VERSION 5.7 ;

  DIVIDERCHAR "/" ;
  BUSBITCHARS "[]" ;
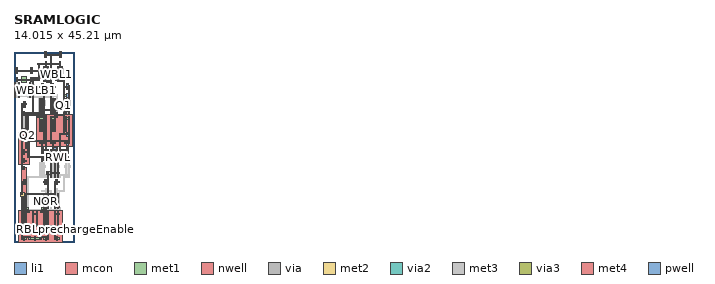
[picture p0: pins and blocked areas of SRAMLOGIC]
MACRO SRAMLOGIC
  CLASS BLOCK ;
  FOREIGN SRAMLOGIC ;
  ORIGIN -0.605 0.000 ;
  SIZE 14.015 BY 45.210 ;
  PIN WWL
    ANTENNAGATEAREA 1.008000 ;
    PORT
      LAYER li1 ;
        RECT 1.165 38.135 1.415 39.145 ;
        RECT 4.605 38.135 4.855 39.145 ;
        RECT 6.325 38.555 6.575 42.505 ;
        RECT 8.045 41.915 8.295 42.925 ;
        RECT 11.485 41.915 11.735 42.925 ;
      LAYER mcon ;
        RECT 6.365 42.335 6.535 42.505 ;
        RECT 1.205 38.555 1.375 38.725 ;
        RECT 4.645 38.555 4.815 38.725 ;
        RECT 8.085 42.335 8.255 42.505 ;
        RECT 11.525 42.335 11.695 42.505 ;
        RECT 6.365 38.555 6.535 38.725 ;
      LAYER met1 ;
        RECT 6.280 42.280 11.780 42.560 ;
        RECT 2.380 38.780 3.550 39.270 ;
        RECT 1.120 38.500 6.620 38.780 ;
        RECT 2.380 37.980 3.550 38.500 ;
    END
  END WWL
  PIN VDD
    ANTENNADIFFAREA 3.749200 ;
    PORT
      LAYER nwell ;
        RECT 1.720 18.480 4.300 26.040 ;
        RECT 6.020 22.680 14.620 30.240 ;
        RECT 11.000 22.670 12.420 22.680 ;
        RECT 1.720 0.000 12.040 7.560 ;
      LAYER li1 ;
        RECT 6.755 26.375 7.005 29.905 ;
        RECT 7.615 26.375 7.865 29.905 ;
        RECT 9.335 26.375 9.585 29.905 ;
        RECT 10.195 26.375 10.445 29.905 ;
        RECT 12.775 26.375 13.025 29.905 ;
        RECT 13.635 26.375 13.885 29.905 ;
        RECT 2.455 22.175 2.705 25.705 ;
        RECT 3.315 22.175 3.565 25.705 ;
        RECT 7.185 23.015 7.435 24.025 ;
        RECT 9.765 23.015 10.015 24.025 ;
        RECT 13.205 23.015 13.455 24.025 ;
        RECT 2.885 18.815 3.135 19.825 ;
        RECT 2.455 3.695 2.705 7.225 ;
        RECT 3.315 3.695 3.565 7.225 ;
        RECT 7.615 3.695 7.865 7.225 ;
        RECT 8.475 3.695 8.725 7.225 ;
        RECT 10.195 3.695 10.445 7.225 ;
        RECT 11.055 3.695 11.305 7.225 ;
        RECT 2.885 0.335 3.135 1.345 ;
        RECT 5.465 0.335 5.715 1.345 ;
        RECT 8.045 0.335 8.295 1.345 ;
        RECT 10.625 0.335 10.875 1.345 ;
      LAYER mcon ;
        RECT 6.795 29.315 6.965 29.485 ;
        RECT 7.655 29.315 7.825 29.485 ;
        RECT 9.375 29.315 9.545 29.485 ;
        RECT 10.235 29.315 10.405 29.485 ;
        RECT 12.815 29.315 12.985 29.485 ;
        RECT 13.675 29.315 13.845 29.485 ;
        RECT 2.495 25.115 2.665 25.285 ;
        RECT 3.355 25.115 3.525 25.285 ;
        RECT 7.225 23.435 7.395 23.605 ;
        RECT 9.805 23.435 9.975 23.605 ;
        RECT 13.245 23.435 13.415 23.605 ;
        RECT 2.925 19.235 3.095 19.405 ;
        RECT 2.495 6.635 2.665 6.805 ;
        RECT 3.355 6.635 3.525 6.805 ;
        RECT 7.655 6.635 7.825 6.805 ;
        RECT 8.515 6.635 8.685 6.805 ;
        RECT 10.235 6.635 10.405 6.805 ;
        RECT 11.095 6.635 11.265 6.805 ;
        RECT 2.925 0.755 3.095 0.925 ;
        RECT 5.505 0.755 5.675 0.925 ;
        RECT 8.085 0.755 8.255 0.925 ;
        RECT 10.665 0.755 10.835 0.925 ;
      LAYER met1 ;
        RECT 6.710 29.260 7.910 29.540 ;
        RECT 9.290 29.260 10.490 29.540 ;
        RECT 12.730 29.260 13.930 29.540 ;
        RECT 2.410 25.060 3.610 25.340 ;
        RECT 2.420 23.800 13.920 24.080 ;
        RECT 6.710 23.380 7.910 23.660 ;
        RECT 9.290 23.380 10.490 23.660 ;
        RECT 12.730 23.380 13.930 23.660 ;
        RECT 2.410 19.180 3.610 19.460 ;
        RECT 2.410 6.580 3.610 6.860 ;
        RECT 7.570 6.580 8.770 6.860 ;
        RECT 10.150 6.580 11.350 6.860 ;
        RECT 8.440 3.640 10.480 3.920 ;
        RECT 2.420 1.120 4.460 1.400 ;
        RECT 6.720 1.120 8.760 1.400 ;
        RECT 4.660 0.980 5.210 1.110 ;
        RECT 2.410 0.700 3.610 0.980 ;
        RECT 4.140 0.700 7.040 0.980 ;
        RECT 7.570 0.700 8.770 0.980 ;
        RECT 10.150 0.700 11.350 0.980 ;
        RECT 4.660 0.510 5.210 0.700 ;
      LAYER via ;
        RECT 7.610 29.270 7.870 29.530 ;
        RECT 9.330 29.270 9.590 29.530 ;
        RECT 13.630 29.270 13.890 29.530 ;
        RECT 2.450 25.070 2.710 25.330 ;
        RECT 2.450 23.810 2.710 24.070 ;
        RECT 7.610 23.810 7.870 24.070 ;
        RECT 9.330 23.810 9.590 24.070 ;
        RECT 13.630 23.810 13.890 24.070 ;
        RECT 7.610 23.390 7.870 23.650 ;
        RECT 9.330 23.390 9.590 23.650 ;
        RECT 13.630 23.390 13.890 23.650 ;
        RECT 2.450 19.190 2.710 19.450 ;
        RECT 2.450 6.590 2.710 6.850 ;
        RECT 8.470 6.590 8.730 6.850 ;
        RECT 10.190 6.590 10.450 6.850 ;
        RECT 8.470 3.650 8.730 3.910 ;
        RECT 10.190 3.650 10.450 3.910 ;
        RECT 2.450 1.130 2.710 1.390 ;
        RECT 4.170 1.130 4.430 1.390 ;
        RECT 6.750 1.130 7.010 1.390 ;
        RECT 8.470 1.130 8.730 1.390 ;
        RECT 2.450 0.710 2.710 0.970 ;
        RECT 4.170 0.710 4.430 0.970 ;
        RECT 6.750 0.710 7.010 0.970 ;
        RECT 8.470 0.710 8.730 0.970 ;
        RECT 10.190 0.710 10.450 0.970 ;
      LAYER met2 ;
        RECT 2.440 17.455 2.720 25.360 ;
        RECT 7.600 23.360 7.880 29.560 ;
        RECT 9.320 23.360 9.600 29.560 ;
        RECT 13.620 23.360 13.900 29.560 ;
        RECT 2.440 0.680 2.720 7.745 ;
        RECT 4.160 0.680 4.440 1.420 ;
        RECT 6.740 0.680 7.020 1.420 ;
        RECT 8.460 0.680 8.740 6.880 ;
        RECT 10.180 0.680 10.460 6.880 ;
      LAYER via2 ;
        RECT 2.440 17.500 2.720 17.780 ;
        RECT 2.440 7.420 2.720 7.700 ;
      LAYER met3 ;
        RECT 2.415 17.240 3.125 18.040 ;
        RECT 2.415 7.160 3.125 7.960 ;
      LAYER via3 ;
        RECT 2.800 17.480 3.120 17.800 ;
        RECT 2.800 7.400 3.120 7.720 ;
      LAYER met4 ;
        RECT 2.370 7.395 3.550 17.805 ;
    END
  END VDD
  PIN WBLB1
    ANTENNADIFFAREA 0.445200 ;
    PORT
      LAYER li1 ;
        RECT 4.175 34.355 4.425 37.885 ;
        RECT 5.035 34.355 5.285 37.885 ;
      LAYER mcon ;
        RECT 4.215 35.195 4.385 35.365 ;
        RECT 5.075 35.195 5.245 35.365 ;
      LAYER met1 ;
        RECT 4.490 35.420 5.040 35.650 ;
        RECT 4.130 35.140 5.330 35.420 ;
    END
  END WBLB1
  PIN WBL2
    ANTENNADIFFAREA 0.235200 ;
    PORT
      LAYER li1 ;
        RECT 8.045 38.135 8.295 41.665 ;
      LAYER mcon ;
        RECT 8.085 38.135 8.255 38.305 ;
      LAYER met1 ;
        RECT 8.350 38.360 8.970 38.520 ;
        RECT 8.000 38.080 9.200 38.360 ;
        RECT 8.350 37.900 8.970 38.080 ;
    END
  END WBL2
  PIN WBL1
    ANTENNADIFFAREA 0.235200 ;
    PORT
      LAYER li1 ;
        RECT 11.485 38.135 11.735 41.665 ;
      LAYER mcon ;
        RECT 11.525 38.555 11.695 38.725 ;
      LAYER met1 ;
        RECT 10.890 38.780 11.340 38.850 ;
        RECT 10.580 38.500 11.780 38.780 ;
        RECT 10.890 38.390 11.340 38.500 ;
    END
  END WBL1
  PIN WBLB2
    ANTENNADIFFAREA 0.445200 ;
    PORT
      LAYER li1 ;
        RECT 0.735 34.355 0.985 37.885 ;
        RECT 1.595 34.355 1.845 37.885 ;
      LAYER mcon ;
        RECT 0.775 35.615 0.945 35.785 ;
        RECT 1.635 35.615 1.805 35.785 ;
      LAYER met1 ;
        RECT 0.950 35.840 1.600 35.990 ;
        RECT 0.690 35.560 1.890 35.840 ;
        RECT 0.950 35.340 1.600 35.560 ;
    END
  END WBLB2
  PIN GND
    ANTENNADIFFAREA 5.644800 ;
    PORT
      LAYER pwell ;
        RECT 7.955 43.830 8.385 45.210 ;
        RECT 11.395 43.830 11.825 45.210 ;
        RECT 1.075 40.050 1.505 41.430 ;
        RECT 4.515 40.050 4.945 41.430 ;
        RECT 7.095 36.270 7.525 37.650 ;
        RECT 9.675 36.270 10.105 37.650 ;
        RECT 13.115 36.270 13.545 37.650 ;
        RECT 2.795 32.070 3.225 33.450 ;
        RECT 7.095 21.150 7.525 22.530 ;
        RECT 9.675 21.150 10.965 22.530 ;
        RECT 13.115 21.150 13.545 22.530 ;
        RECT 2.795 13.590 3.225 14.970 ;
        RECT 7.955 13.590 8.385 14.970 ;
        RECT 10.535 13.590 10.965 14.970 ;
      LAYER li1 ;
        RECT 8.045 44.015 8.295 45.025 ;
        RECT 11.485 44.015 11.735 45.025 ;
        RECT 1.165 40.235 1.415 41.245 ;
        RECT 4.605 40.235 4.855 41.245 ;
        RECT 7.185 36.455 7.435 37.465 ;
        RECT 9.765 36.455 10.015 37.465 ;
        RECT 13.205 36.455 13.455 37.465 ;
        RECT 2.885 32.255 3.135 33.265 ;
        RECT 6.755 30.575 7.005 34.105 ;
        RECT 7.615 30.575 7.865 34.105 ;
        RECT 9.335 30.575 9.585 34.105 ;
        RECT 10.195 30.575 10.445 34.105 ;
        RECT 12.775 30.575 13.025 34.105 ;
        RECT 13.635 30.575 13.885 34.105 ;
        RECT 2.455 26.375 2.705 29.905 ;
        RECT 3.315 26.375 3.565 29.905 ;
        RECT 7.185 21.335 7.435 22.345 ;
        RECT 8.475 21.335 8.725 21.925 ;
        RECT 9.765 21.335 10.015 22.345 ;
        RECT 10.625 21.335 10.875 22.345 ;
        RECT 11.485 21.335 11.735 21.925 ;
        RECT 13.205 21.335 13.455 22.345 ;
        RECT 9.335 15.455 9.585 18.985 ;
        RECT 10.195 15.455 10.445 18.985 ;
        RECT 11.055 15.455 11.305 18.985 ;
        RECT 2.885 13.775 3.135 14.785 ;
        RECT 8.045 13.775 8.295 14.785 ;
        RECT 10.625 13.775 10.875 14.785 ;
        RECT 2.455 7.895 2.705 11.425 ;
        RECT 3.315 7.895 3.565 11.425 ;
        RECT 7.615 7.895 7.865 11.425 ;
        RECT 8.475 7.895 8.725 11.425 ;
        RECT 10.195 7.895 10.445 11.425 ;
        RECT 11.055 7.895 11.305 11.425 ;
      LAYER mcon ;
        RECT 8.085 44.435 8.255 44.605 ;
        RECT 11.525 44.435 11.695 44.605 ;
        RECT 1.205 40.655 1.375 40.825 ;
        RECT 4.645 40.655 4.815 40.825 ;
        RECT 7.225 36.875 7.395 37.045 ;
        RECT 9.805 36.875 9.975 37.045 ;
        RECT 13.245 36.875 13.415 37.045 ;
        RECT 2.925 32.675 3.095 32.845 ;
        RECT 6.795 30.995 6.965 31.165 ;
        RECT 7.655 30.995 7.825 31.165 ;
        RECT 9.375 30.995 9.545 31.165 ;
        RECT 10.235 30.995 10.405 31.165 ;
        RECT 12.815 30.995 12.985 31.165 ;
        RECT 13.675 30.995 13.845 31.165 ;
        RECT 2.495 26.795 2.665 26.965 ;
        RECT 3.355 26.795 3.525 26.965 ;
        RECT 7.225 21.755 7.395 21.925 ;
        RECT 8.515 21.755 8.685 21.925 ;
        RECT 8.515 21.335 8.685 21.505 ;
        RECT 9.805 21.755 9.975 21.925 ;
        RECT 10.665 21.755 10.835 21.925 ;
        RECT 11.525 21.755 11.695 21.925 ;
        RECT 11.525 21.335 11.695 21.505 ;
        RECT 13.245 21.755 13.415 21.925 ;
        RECT 9.375 16.295 9.545 16.465 ;
        RECT 10.235 16.295 10.405 16.465 ;
        RECT 11.095 16.295 11.265 16.465 ;
        RECT 2.925 14.195 3.095 14.365 ;
        RECT 8.085 14.195 8.255 14.365 ;
        RECT 10.665 14.195 10.835 14.365 ;
        RECT 2.495 8.315 2.665 8.485 ;
        RECT 3.355 8.315 3.525 8.485 ;
        RECT 7.655 8.315 7.825 8.485 ;
        RECT 8.515 8.315 8.685 8.485 ;
        RECT 10.235 8.315 10.405 8.485 ;
        RECT 11.095 8.315 11.265 8.485 ;
      LAYER met1 ;
        RECT 8.000 44.380 11.780 44.660 ;
        RECT 2.550 40.880 3.280 40.890 ;
        RECT 1.120 40.600 9.620 40.880 ;
        RECT 2.550 40.590 3.280 40.600 ;
        RECT 6.710 36.820 7.910 37.100 ;
        RECT 9.290 36.820 10.490 37.100 ;
        RECT 12.730 36.820 13.930 37.100 ;
        RECT 2.410 32.620 3.610 32.900 ;
        RECT 7.580 31.360 13.920 31.640 ;
        RECT 6.710 30.940 7.910 31.220 ;
        RECT 9.290 30.940 10.490 31.220 ;
        RECT 12.730 30.940 13.930 31.220 ;
        RECT 2.420 30.100 8.330 30.380 ;
        RECT 2.410 26.740 3.610 27.020 ;
        RECT 7.140 21.700 8.770 21.980 ;
        RECT 9.290 21.700 10.920 21.980 ;
        RECT 11.440 21.700 13.500 21.980 ;
        RECT 8.430 21.280 11.780 21.560 ;
        RECT 9.290 16.240 11.350 16.520 ;
        RECT 2.410 14.140 3.610 14.420 ;
        RECT 7.570 14.140 8.770 14.420 ;
        RECT 10.150 14.140 11.350 14.420 ;
        RECT 2.420 11.200 10.480 11.480 ;
        RECT 2.410 8.260 3.610 8.540 ;
        RECT 7.570 8.260 8.770 8.540 ;
        RECT 10.150 8.260 11.350 8.540 ;
      LAYER via ;
        RECT 9.330 44.390 9.590 44.650 ;
        RECT 9.330 40.610 9.590 40.870 ;
        RECT 7.610 36.830 7.870 37.090 ;
        RECT 9.330 36.830 9.590 37.090 ;
        RECT 13.630 36.830 13.890 37.090 ;
        RECT 2.450 32.630 2.710 32.890 ;
        RECT 7.610 31.370 7.870 31.630 ;
        RECT 9.330 31.370 9.590 31.630 ;
        RECT 13.630 31.370 13.890 31.630 ;
        RECT 7.610 30.950 7.870 31.210 ;
        RECT 9.330 30.950 9.590 31.210 ;
        RECT 13.630 30.950 13.890 31.210 ;
        RECT 2.450 30.110 2.710 30.370 ;
        RECT 7.610 30.110 7.870 30.370 ;
        RECT 8.040 30.110 8.300 30.370 ;
        RECT 2.450 26.750 2.710 27.010 ;
        RECT 8.040 21.710 8.300 21.970 ;
        RECT 9.330 21.710 9.590 21.970 ;
        RECT 9.330 21.290 9.590 21.550 ;
        RECT 9.330 16.250 9.590 16.510 ;
        RECT 2.450 14.150 2.710 14.410 ;
        RECT 8.470 14.150 8.730 14.410 ;
        RECT 10.190 14.150 10.450 14.410 ;
        RECT 2.450 11.210 2.710 11.470 ;
        RECT 8.470 11.210 8.730 11.470 ;
        RECT 10.190 11.210 10.450 11.470 ;
        RECT 2.450 8.270 2.710 8.530 ;
        RECT 8.470 8.270 8.730 8.530 ;
        RECT 10.190 8.270 10.450 8.530 ;
      LAYER met2 ;
        RECT 2.440 26.720 2.720 32.920 ;
        RECT 7.600 30.080 7.880 37.120 ;
        RECT 9.320 30.920 9.600 44.680 ;
        RECT 13.620 30.920 13.900 37.120 ;
        RECT 8.030 21.680 8.310 30.400 ;
        RECT 2.440 11.670 2.720 14.440 ;
        RECT 2.090 10.930 2.990 11.670 ;
        RECT 2.440 8.240 2.720 10.930 ;
        RECT 8.460 8.240 8.740 16.565 ;
        RECT 9.320 16.195 9.600 22.000 ;
        RECT 10.180 8.240 10.460 14.440 ;
      LAYER via2 ;
        RECT 8.460 16.240 8.740 16.520 ;
        RECT 9.320 16.240 9.600 16.520 ;
      LAYER met3 ;
        RECT 8.435 15.980 9.625 16.780 ;
    END
  END GND
  PIN Q1
    ANTENNAGATEAREA 0.504000 ;
    ANTENNADIFFAREA 0.798000 ;
    PORT
      LAYER li1 ;
        RECT 11.055 38.135 11.305 41.665 ;
        RECT 11.915 38.135 12.165 41.665 ;
        RECT 9.765 30.575 10.015 34.105 ;
        RECT 9.765 26.375 10.015 29.905 ;
        RECT 12.345 25.535 12.595 39.565 ;
        RECT 13.205 34.355 13.455 35.365 ;
        RECT 13.205 25.115 13.455 26.125 ;
        RECT 10.625 19.235 10.875 20.245 ;
      LAYER mcon ;
        RECT 11.095 39.395 11.265 39.565 ;
        RECT 11.955 39.395 12.125 39.565 ;
        RECT 12.385 39.395 12.555 39.565 ;
        RECT 12.385 34.775 12.555 34.945 ;
        RECT 9.805 30.575 9.975 30.745 ;
        RECT 13.245 34.775 13.415 34.945 ;
        RECT 12.385 30.155 12.555 30.325 ;
        RECT 9.805 29.735 9.975 29.905 ;
        RECT 12.385 25.535 12.555 25.705 ;
        RECT 13.245 25.535 13.415 25.705 ;
        RECT 10.665 19.655 10.835 19.825 ;
      LAYER met1 ;
        RECT 11.010 39.340 12.640 39.620 ;
        RECT 12.300 34.720 13.500 35.000 ;
        RECT 9.720 30.520 10.920 30.800 ;
        RECT 10.160 30.100 12.640 30.380 ;
        RECT 9.720 29.680 10.920 29.960 ;
        RECT 11.450 25.480 13.500 25.760 ;
        RECT 10.580 19.600 11.780 19.880 ;
        RECT 11.030 19.300 11.480 19.600 ;
      LAYER via ;
        RECT 10.190 30.530 10.450 30.790 ;
        RECT 10.190 30.110 10.450 30.370 ;
        RECT 10.190 29.690 10.450 29.950 ;
        RECT 11.480 25.490 11.740 25.750 ;
        RECT 11.480 19.610 11.740 19.870 ;
      LAYER met2 ;
        RECT 10.180 29.660 10.460 30.820 ;
        RECT 11.470 19.580 11.750 25.780 ;
    END
  END Q1
  PIN Q2
    ANTENNAGATEAREA 0.504000 ;
    ANTENNADIFFAREA 0.798000 ;
    PORT
      LAYER li1 ;
        RECT 7.615 38.135 7.865 41.665 ;
        RECT 8.475 38.135 8.725 41.665 ;
        RECT 2.885 30.155 3.135 31.165 ;
        RECT 2.885 20.915 3.135 21.925 ;
        RECT 3.745 20.075 3.995 30.745 ;
        RECT 5.035 30.575 5.285 34.105 ;
        RECT 7.185 30.575 7.435 34.105 ;
        RECT 7.185 26.375 7.435 29.905 ;
        RECT 9.765 19.235 10.015 20.245 ;
      LAYER mcon ;
        RECT 7.655 38.975 7.825 39.145 ;
        RECT 8.515 38.975 8.685 39.145 ;
        RECT 5.075 33.935 5.245 34.105 ;
        RECT 2.925 30.575 3.095 30.745 ;
        RECT 3.785 30.575 3.955 30.745 ;
        RECT 5.075 30.575 5.245 30.745 ;
        RECT 7.225 30.575 7.395 30.745 ;
        RECT 2.925 21.335 3.095 21.505 ;
        RECT 7.225 29.735 7.395 29.905 ;
        RECT 3.785 21.335 3.955 21.505 ;
        RECT 3.785 20.075 3.955 20.245 ;
        RECT 9.805 20.075 9.975 20.245 ;
      LAYER met1 ;
        RECT 5.000 38.920 8.770 39.200 ;
        RECT 4.990 33.880 5.330 34.160 ;
        RECT 2.840 30.520 7.480 30.800 ;
        RECT 6.280 29.680 7.480 29.960 ;
        RECT 2.840 21.280 4.040 21.560 ;
        RECT 10.120 20.300 10.570 20.910 ;
        RECT 3.700 20.020 10.920 20.300 ;
      LAYER via ;
        RECT 5.030 38.930 5.290 39.190 ;
        RECT 5.030 33.890 5.290 34.150 ;
        RECT 6.750 30.530 7.010 30.790 ;
        RECT 6.750 29.690 7.010 29.950 ;
      LAYER met2 ;
        RECT 5.020 33.860 5.300 39.220 ;
        RECT 6.740 29.660 7.020 30.820 ;
    END
  END Q2
  PIN RWL
    ANTENNAGATEAREA 0.252000 ;
    PORT
      LAYER li1 ;
        RECT 7.185 19.235 7.435 20.245 ;
        RECT 13.205 19.235 13.455 20.245 ;
      LAYER mcon ;
        RECT 7.225 19.655 7.395 19.825 ;
        RECT 13.245 19.655 13.415 19.825 ;
      LAYER met1 ;
        RECT 7.140 19.600 10.050 19.880 ;
        RECT 12.300 19.600 13.500 19.880 ;
        RECT 7.710 19.430 8.320 19.600 ;
      LAYER via ;
        RECT 9.760 19.610 10.020 19.870 ;
        RECT 12.340 19.610 12.600 19.870 ;
      LAYER met2 ;
        RECT 9.750 19.580 10.030 20.345 ;
        RECT 12.330 19.580 12.610 20.345 ;
      LAYER via2 ;
        RECT 9.750 20.020 10.030 20.300 ;
        RECT 12.330 20.020 12.610 20.300 ;
      LAYER met3 ;
        RECT 9.725 19.760 12.635 20.560 ;
    END
  END RWL
  PIN RBLprechargeEnable
    ANTENNAGATEAREA 0.252000 ;
    PORT
      LAYER li1 ;
        RECT 5.465 2.435 5.715 3.445 ;
      LAYER mcon ;
        RECT 5.505 2.855 5.675 3.025 ;
      LAYER met1 ;
        RECT 4.550 3.080 5.070 3.220 ;
        RECT 4.550 2.800 5.760 3.080 ;
        RECT 4.550 2.620 5.070 2.800 ;
    END
  END RBLprechargeEnable
  PIN RBLprecharge
    ANTENNADIFFAREA 0.445200 ;
    PORT
      LAYER li1 ;
        RECT 5.035 3.695 5.285 7.225 ;
        RECT 5.895 3.695 6.145 7.225 ;
      LAYER mcon ;
        RECT 5.075 6.635 5.245 6.805 ;
        RECT 5.935 6.635 6.105 6.805 ;
      LAYER met1 ;
        RECT 4.990 6.580 6.190 6.860 ;
        RECT 5.380 6.470 5.800 6.580 ;
    END
  END RBLprecharge
  PIN NOR
    ANTENNADIFFAREA 0.352800 ;
    PORT
      LAYER li1 ;
        RECT 8.045 7.895 8.295 11.425 ;
        RECT 8.045 3.695 8.295 7.225 ;
      LAYER mcon ;
        RECT 8.085 7.895 8.255 8.065 ;
        RECT 8.085 7.055 8.255 7.225 ;
      LAYER met1 ;
        RECT 7.140 7.840 8.340 8.120 ;
        RECT 6.960 7.000 8.340 7.280 ;
        RECT 6.960 6.960 7.330 7.000 ;
      LAYER via ;
        RECT 7.610 7.850 7.870 8.110 ;
        RECT 7.610 7.010 7.870 7.270 ;
      LAYER met2 ;
        RECT 7.600 6.980 7.880 8.140 ;
    END
  END NOR
  PIN OR
    ANTENNADIFFAREA 0.352800 ;
    PORT
      LAYER li1 ;
        RECT 2.885 7.895 3.135 11.425 ;
        RECT 2.885 3.695 3.135 7.225 ;
      LAYER mcon ;
        RECT 2.925 7.895 3.095 8.065 ;
        RECT 2.925 7.055 3.095 7.225 ;
      LAYER met1 ;
        RECT 2.840 7.840 4.040 8.120 ;
        RECT 2.840 7.000 4.290 7.280 ;
        RECT 3.810 6.930 4.290 7.000 ;
      LAYER via ;
        RECT 3.310 7.850 3.570 8.110 ;
        RECT 3.310 7.010 3.570 7.270 ;
      LAYER met2 ;
        RECT 3.300 6.980 3.580 8.140 ;
    END
  END OR
  OBS
      LAYER pwell ;
        RECT 7.485 40.085 8.855 41.185 ;
        RECT 10.925 40.085 12.295 41.185 ;
        RECT 0.605 36.305 1.975 37.405 ;
        RECT 4.045 36.305 5.415 37.405 ;
        RECT 6.625 32.525 7.995 33.625 ;
        RECT 9.205 32.525 10.575 33.625 ;
        RECT 12.645 32.525 14.015 33.625 ;
        RECT 2.325 28.325 3.695 29.425 ;
        RECT 6.625 17.615 7.995 18.295 ;
        RECT 9.205 17.615 11.435 18.295 ;
        RECT 12.645 17.615 14.015 18.295 ;
        RECT 2.325 10.055 3.695 10.735 ;
        RECT 7.485 10.055 8.855 10.735 ;
        RECT 10.065 10.055 11.435 10.735 ;
      LAYER li1 ;
        RECT 1.165 34.355 1.415 37.885 ;
        RECT 4.605 34.355 4.855 37.885 ;
        RECT 2.885 26.375 3.135 29.905 ;
        RECT 2.885 22.175 3.135 25.705 ;
        RECT 6.325 25.535 6.575 34.945 ;
        RECT 7.185 34.355 7.435 35.365 ;
        RECT 9.765 34.355 10.015 35.365 ;
        RECT 7.185 25.115 7.435 26.125 ;
        RECT 9.765 25.115 10.015 26.125 ;
        RECT 10.625 25.535 10.875 34.945 ;
        RECT 13.205 30.575 13.455 34.105 ;
        RECT 13.205 26.375 13.455 29.905 ;
        RECT 2.885 11.675 3.135 12.685 ;
        RECT 2.885 2.435 3.135 3.445 ;
        RECT 3.745 2.855 3.995 15.625 ;
        RECT 6.755 15.455 7.005 18.985 ;
        RECT 7.185 15.455 7.435 18.985 ;
        RECT 7.615 15.455 7.865 18.985 ;
        RECT 9.765 15.455 10.015 18.985 ;
        RECT 10.625 15.455 10.875 18.985 ;
        RECT 11.485 15.455 11.735 16.045 ;
        RECT 8.045 11.675 8.295 12.685 ;
        RECT 4.605 7.055 4.855 7.645 ;
        RECT 5.465 3.695 5.715 7.225 ;
        RECT 8.045 2.435 8.295 3.445 ;
        RECT 9.335 2.855 9.585 12.265 ;
        RECT 10.625 11.675 10.875 12.685 ;
        RECT 12.345 12.095 12.595 15.625 ;
        RECT 12.775 15.455 13.025 18.985 ;
        RECT 13.205 15.455 13.455 18.985 ;
        RECT 13.635 15.455 13.885 18.985 ;
        RECT 10.625 7.895 10.875 11.425 ;
        RECT 10.625 3.695 10.875 7.225 ;
        RECT 10.625 2.435 10.875 3.445 ;
      LAYER mcon ;
        RECT 1.205 34.775 1.375 34.945 ;
        RECT 4.645 34.355 4.815 34.525 ;
        RECT 6.365 34.775 6.535 34.945 ;
        RECT 2.925 26.375 3.095 26.545 ;
        RECT 7.225 34.775 7.395 34.945 ;
        RECT 9.805 34.775 9.975 34.945 ;
        RECT 10.665 34.775 10.835 34.945 ;
        RECT 13.245 30.575 13.415 30.745 ;
        RECT 10.665 28.895 10.835 29.065 ;
        RECT 2.925 25.535 3.095 25.705 ;
        RECT 6.365 25.535 6.535 25.705 ;
        RECT 7.225 25.535 7.395 25.705 ;
        RECT 9.805 25.535 9.975 25.705 ;
        RECT 13.245 29.735 13.415 29.905 ;
        RECT 10.665 25.535 10.835 25.705 ;
        RECT 6.795 15.875 6.965 16.045 ;
        RECT 3.785 15.455 3.955 15.625 ;
        RECT 7.225 15.455 7.395 15.625 ;
        RECT 7.655 15.875 7.825 16.045 ;
        RECT 9.805 15.875 9.975 16.045 ;
        RECT 10.665 15.455 10.835 15.625 ;
        RECT 11.525 15.875 11.695 16.045 ;
        RECT 12.815 15.875 12.985 16.045 ;
        RECT 11.525 15.455 11.695 15.625 ;
        RECT 12.385 15.455 12.555 15.625 ;
        RECT 13.245 15.455 13.415 15.625 ;
        RECT 13.675 15.875 13.845 16.045 ;
        RECT 2.925 12.095 3.095 12.265 ;
        RECT 3.785 12.095 3.955 12.265 ;
        RECT 8.085 12.095 8.255 12.265 ;
        RECT 9.375 12.095 9.545 12.265 ;
        RECT 3.785 7.475 3.955 7.645 ;
        RECT 2.925 2.855 3.095 3.025 ;
        RECT 4.645 7.475 4.815 7.645 ;
        RECT 10.665 12.095 10.835 12.265 ;
        RECT 12.385 12.095 12.555 12.265 ;
        RECT 10.665 7.895 10.835 8.065 ;
        RECT 4.645 7.055 4.815 7.225 ;
        RECT 5.505 7.055 5.675 7.225 ;
        RECT 9.375 7.055 9.545 7.225 ;
        RECT 3.785 2.855 3.955 3.025 ;
        RECT 8.085 2.855 8.255 3.025 ;
        RECT 10.665 7.055 10.835 7.225 ;
        RECT 9.375 2.855 9.545 3.025 ;
        RECT 10.665 2.855 10.835 3.025 ;
      LAYER met1 ;
        RECT 1.120 34.720 7.480 35.000 ;
        RECT 9.720 34.720 10.920 35.000 ;
        RECT 3.700 34.300 10.050 34.580 ;
        RECT 12.300 30.520 13.500 30.800 ;
        RECT 12.300 29.680 13.500 29.960 ;
        RECT 10.580 28.840 12.630 29.120 ;
        RECT 2.840 26.320 4.040 26.600 ;
        RECT 2.840 25.480 7.480 25.760 ;
        RECT 9.720 25.480 10.920 25.760 ;
        RECT 6.710 15.820 10.920 16.100 ;
        RECT 11.440 15.820 13.930 16.100 ;
        RECT 3.700 15.400 8.340 15.680 ;
        RECT 10.580 15.400 11.780 15.680 ;
        RECT 12.300 15.400 13.500 15.680 ;
        RECT 2.840 12.040 4.040 12.320 ;
        RECT 7.140 12.040 9.630 12.320 ;
        RECT 10.580 12.040 12.640 12.320 ;
        RECT 10.580 7.840 11.780 8.120 ;
        RECT 3.700 7.420 11.340 7.700 ;
        RECT 4.560 7.000 5.760 7.280 ;
        RECT 9.290 7.000 11.780 7.280 ;
        RECT 2.840 2.800 4.040 3.080 ;
        RECT 7.140 2.800 9.630 3.080 ;
        RECT 10.580 2.800 11.780 3.080 ;
      LAYER via ;
        RECT 9.760 34.730 10.020 34.990 ;
        RECT 9.760 34.310 10.020 34.570 ;
        RECT 12.770 30.530 13.030 30.790 ;
        RECT 12.340 29.690 12.600 29.950 ;
        RECT 12.770 29.690 13.030 29.950 ;
        RECT 12.340 28.850 12.600 29.110 ;
        RECT 3.310 26.330 3.570 26.590 ;
        RECT 3.310 25.490 3.570 25.750 ;
        RECT 11.050 12.050 11.310 12.310 ;
        RECT 10.620 7.850 10.880 8.110 ;
        RECT 11.050 7.430 11.310 7.690 ;
        RECT 10.620 7.010 10.880 7.270 ;
        RECT 11.050 2.810 11.310 3.070 ;
      LAYER met2 ;
        RECT 9.750 34.280 10.030 35.020 ;
        RECT 12.330 28.820 12.610 29.980 ;
        RECT 12.760 29.660 13.040 30.820 ;
        RECT 3.300 25.460 3.580 26.620 ;
        RECT 10.610 6.980 10.890 8.140 ;
        RECT 11.040 2.780 11.320 12.340 ;
  END
END SRAMLOGIC
END LIBRARY

